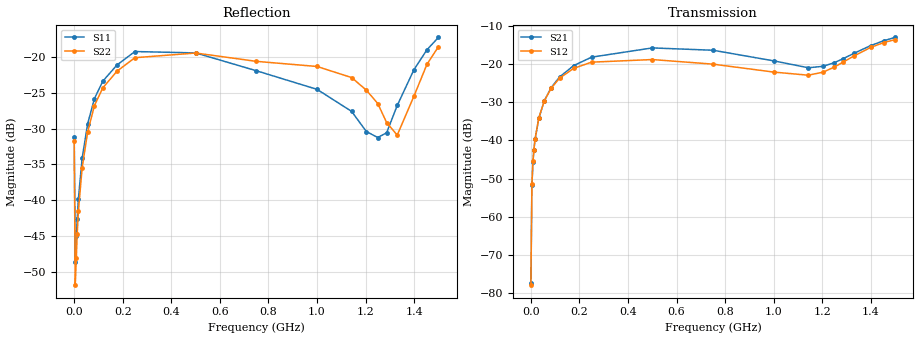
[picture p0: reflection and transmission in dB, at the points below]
!Keysight Technologies,N5232A,MY52221221,A.10.65.11
!Date: Tuesday, May 21, 2024 18:52:51
!Correction: S11(Full 2 Port(1,4))
!S41(Full 2 Port(1,4))
!S14(Full 2 Port(1,4))
!S44(Full 2 Port(1,4))
!S2P File: Measurements: S11, S41, S14, S44:
# Hz S  RI  R 50
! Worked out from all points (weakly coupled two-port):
!   16001 points, 300 kHz to 1.5 GHz, reference 50 ohm
!   highest |S21| = -12.91 dB at 1.5 GHz (marker M1); lowest = -77.5 dB at 300 kHz (marker M2)
!   lowest |S11| = -48.7 dB at 4.612 MHz (marker M3), VSWR 1.01, Z = 50.4 + j0.0863 ohm
!   |S11| at or under -10 dB: start of sweep to end of sweep
!   |S22| runs from -52.3 to -18.6 dB; largest |S21 - S12| = 0.38
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300000  -0.0162 0.0225  -3.54e-05 0.000128  -0.000107 6.61e-05  -0.0157 0.0208
4611638  0.00359 0.000857  -0.000154 0.00262  -0.00254 0.000772  0.00236 0.00101
9110738  0.00411 -0.00381  -6.8e-05 0.00525  -0.00514 0.00177  0.00276 -0.00288
1.257879e7  0.00366 -0.00645  -8.54e-06 0.00754  -0.007 0.00262  0.00258 -0.00524
1.754655e7  0.00301 -0.00978  0.000187 0.0103  -0.00957 0.00418  0.00188 -0.00817
3.291848e7  -0.000564 -0.0196  0.00161 0.0195  -0.0172 0.00976  -0.00187 -0.0167
5.569517e7  -0.00939 -0.0328  0.00536 0.0328  -0.026 0.0206  -0.0114 -0.0277
8.362708e7  -0.024 -0.0451  0.0125 0.0477  -0.0317 0.0367  -0.0271 -0.0368
1.182139e8  -0.0445 -0.0509  0.0246 0.0636  -0.0313 0.0579  -0.0476 -0.0378
1.76421e8  -0.0802 -0.0352  0.0498 0.0825  -0.0127 0.0876  -0.0782 -0.0129
2.502812e8  -0.1087 0.000939  0.0843 0.0914  0.0264 0.1036  -0.0922 0.0345
5.002625e8  -0.0442 0.0967  0.1564 0.0509  0.1101 0.0355  0.0227 0.1037
7.5015e8  0.0246 0.076  0.1533 -0.00168  0.0926 -0.0395  0.0874 0.0314
1.000131e9  0.0497 0.0323  0.1105 -0.0123  0.049 -0.0622  0.0723 -0.0457
1.142603e9  0.0415 -0.00302  0.089 0.0149  0.0443 -0.0568  0.0215 -0.0683
1.203059e9  0.0229 -0.0196  0.0877 0.0345  0.0526 -0.0589  -0.00846 -0.0579
1.250112e9  0.00319 -0.0272  0.0917 0.0517  0.0619 -0.0685  -0.0256 -0.0397
1.286668e9  -0.0171 -0.0241  0.0993 0.0658  0.0698 -0.0816  -0.0305 -0.0167
1.330253e9  -0.0447 -0.00989  0.1136 0.0808  0.0734 -0.1057  -0.0242 0.015
1.399145e9  -0.0722 0.0373  0.1475 0.0968  0.0573 -0.1567  0.0211 0.0488
1.452759e9  -0.0646 0.0914  0.1794 0.0974  0.0162 -0.1925  0.0775 0.043
1.5e9  -0.0347 0.1319  0.2082 0.0884  -0.0342 -0.2086  0.1173 0.0075
